VERSION 5.7 ;
  NOWIREEXTENSIONATPIN ON ;
  DIVIDERCHAR "/" ;
  BUSBITCHARS "[]" ;
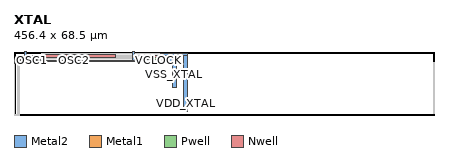
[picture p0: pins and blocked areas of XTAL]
MACRO XTAL
  CLASS BLOCK ;
  FOREIGN XTAL ;
  ORIGIN 0.000 0.000 ;
  SIZE 456.400 BY 68.500 ;
  PIN OSC2
    ANTENNAGATEAREA 2.352000 ;
    ANTENNADIFFAREA 48.399998 ;
    PORT
      LAYER Metal2 ;
        RECT 129.000 59.500 131.020 68.500 ;
        RECT 0.000 58.500 131.020 59.500 ;
        RECT 0.000 55.900 1.000 58.500 ;
    END
  END OSC2
  PIN VCLOCK
    ANTENNADIFFAREA 6.583500 ;
    PORT
      LAYER Metal1 ;
        RECT 143.910 63.165 144.140 64.020 ;
        RECT 145.510 63.165 145.740 64.020 ;
        RECT 147.110 63.165 147.340 64.020 ;
        RECT 143.910 62.935 147.340 63.165 ;
        RECT 147.110 62.665 147.340 62.935 ;
        RECT 148.725 62.665 148.955 64.020 ;
        RECT 150.325 62.665 150.555 64.020 ;
        RECT 151.925 62.665 152.155 64.020 ;
        RECT 147.110 62.600 152.155 62.665 ;
        RECT 147.110 62.250 167.075 62.600 ;
        RECT 147.110 62.160 152.155 62.250 ;
        RECT 147.110 61.960 147.340 62.160 ;
        RECT 143.910 61.730 147.340 61.960 ;
        RECT 143.910 61.160 144.140 61.730 ;
        RECT 145.510 61.160 145.740 61.730 ;
        RECT 147.110 61.160 147.340 61.730 ;
        RECT 148.725 61.160 148.955 62.160 ;
        RECT 150.325 61.160 150.555 62.160 ;
        RECT 151.925 61.160 152.155 62.160 ;
    END
  END VCLOCK
  PIN VSS_XTAL
    ANTENNADIFFAREA 40.156399 ;
    PORT
      LAYER Pwell ;
        RECT 137.295 60.200 156.115 62.400 ;
      LAYER Metal2 ;
        RECT 3.400 60.000 28.880 61.000 ;
        RECT 161.475 58.340 176.815 60.930 ;
        RECT 171.775 30.200 176.815 58.340 ;
    END
  END VSS_XTAL
  PIN VDD_XTAL
    ANTENNADIFFAREA 78.429695 ;
    PORT
      LAYER Nwell ;
        RECT 29.880 63.000 110.740 65.470 ;
        RECT 137.295 62.400 156.115 64.980 ;
      LAYER Metal2 ;
        RECT 158.655 64.250 189.075 66.835 ;
        RECT 184.075 4.045 189.075 64.250 ;
    END
  END VDD_XTAL
  PIN OSC1
    ANTENNAGATEAREA 30.799999 ;
    PORT
      LAYER Metal2 ;
        RECT 11.510 64.150 13.380 68.500 ;
        RECT 5.230 62.250 25.880 64.150 ;
    END
  END OSC1
  OBS
      LAYER Metal1 ;
        RECT 30.300 64.250 160.625 66.835 ;
        RECT 30.300 64.220 110.320 64.250 ;
        RECT 0.000 0.750 1.000 59.500 ;
        RECT 3.400 1.100 4.600 61.000 ;
        RECT 5.230 56.405 5.730 64.150 ;
        RECT 25.380 62.250 29.380 64.150 ;
        RECT 28.290 61.360 29.380 62.250 ;
        RECT 30.300 62.535 137.295 63.800 ;
        RECT 138.100 62.865 138.440 64.250 ;
        RECT 139.910 63.480 140.140 64.250 ;
        RECT 140.710 63.165 140.940 64.020 ;
        RECT 141.510 63.395 141.740 64.250 ;
        RECT 142.310 63.165 142.540 64.020 ;
        RECT 143.110 63.400 143.340 64.250 ;
        RECT 144.710 63.400 144.940 64.250 ;
        RECT 146.310 63.395 146.540 64.250 ;
        RECT 140.710 62.935 143.310 63.165 ;
        RECT 140.220 62.535 142.850 62.705 ;
        RECT 30.300 62.285 142.850 62.535 ;
        RECT 30.300 62.090 137.295 62.285 ;
        RECT 140.220 62.200 142.850 62.285 ;
        RECT 143.080 62.550 143.310 62.935 ;
        RECT 147.910 62.895 148.140 64.250 ;
        RECT 149.525 62.895 149.755 64.250 ;
        RECT 151.125 62.895 151.355 64.250 ;
        RECT 152.725 62.895 152.955 64.250 ;
        RECT 154.940 62.865 155.280 64.250 ;
        RECT 143.080 62.260 146.880 62.550 ;
        RECT 30.100 61.710 137.295 62.090 ;
        RECT 30.100 61.000 60.340 61.290 ;
        RECT 27.880 60.930 60.340 61.000 ;
        RECT 138.100 60.930 138.440 62.010 ;
        RECT 143.080 61.960 143.310 62.260 ;
        RECT 140.710 61.730 143.310 61.960 ;
        RECT 139.910 60.930 140.140 61.330 ;
        RECT 140.710 61.160 140.940 61.730 ;
        RECT 141.510 60.930 141.740 61.340 ;
        RECT 142.310 61.160 142.540 61.730 ;
        RECT 143.110 60.930 143.340 61.340 ;
        RECT 144.710 60.930 144.940 61.340 ;
        RECT 146.310 60.930 146.540 61.340 ;
        RECT 147.910 60.930 148.140 61.320 ;
        RECT 149.525 60.930 149.755 61.320 ;
        RECT 151.125 60.930 151.355 61.320 ;
        RECT 152.725 60.930 152.955 61.320 ;
        RECT 154.940 60.930 155.280 62.010 ;
        RECT 27.880 58.340 163.475 60.930 ;
        RECT 5.380 52.595 5.730 55.345 ;
        RECT 456.050 54.495 456.400 57.245 ;
        RECT 5.380 48.795 5.730 51.545 ;
        RECT 456.050 50.695 456.400 53.445 ;
        RECT 5.380 44.995 5.730 47.745 ;
        RECT 456.050 46.895 456.400 49.645 ;
        RECT 5.380 41.195 5.730 43.945 ;
        RECT 456.050 43.095 456.400 45.845 ;
        RECT 5.380 37.395 5.730 40.145 ;
        RECT 456.050 39.295 456.400 42.045 ;
        RECT 5.380 33.595 5.730 36.345 ;
        RECT 456.050 35.495 456.400 38.245 ;
        RECT 5.380 29.795 5.730 32.545 ;
        RECT 456.050 31.695 456.400 34.445 ;
        RECT 5.380 25.995 5.730 28.745 ;
        RECT 456.050 27.895 456.400 30.645 ;
        RECT 5.380 22.195 5.730 24.945 ;
        RECT 456.050 24.095 456.400 26.845 ;
        RECT 5.380 18.395 5.730 21.145 ;
        RECT 456.050 20.295 456.400 23.045 ;
        RECT 5.380 14.595 5.730 17.345 ;
        RECT 456.050 16.495 456.400 19.245 ;
        RECT 5.380 10.795 5.730 13.545 ;
        RECT 456.050 12.695 456.400 15.445 ;
        RECT 5.380 6.995 5.730 9.745 ;
        RECT 456.050 8.895 456.400 11.645 ;
        RECT 5.380 3.195 5.730 5.945 ;
        RECT 456.050 5.095 456.400 7.845 ;
        RECT 5.300 0.750 5.730 2.200 ;
        RECT 456.050 1.295 456.400 4.045 ;
        RECT 0.000 0.000 5.730 0.750 ;
      LAYER Via1 ;
        RECT 158.930 66.370 159.190 66.630 ;
        RECT 159.475 66.370 159.735 66.630 ;
        RECT 160.035 66.370 160.295 66.630 ;
        RECT 158.935 65.720 159.195 65.980 ;
        RECT 159.475 65.720 159.735 65.980 ;
        RECT 160.035 65.720 160.295 65.980 ;
        RECT 158.935 65.120 159.195 65.380 ;
        RECT 159.475 65.120 159.735 65.380 ;
        RECT 160.035 65.120 160.295 65.380 ;
        RECT 158.935 64.520 159.195 64.780 ;
        RECT 159.475 64.520 159.735 64.780 ;
        RECT 160.035 64.520 160.295 64.780 ;
        RECT 5.350 63.690 5.610 63.950 ;
        RECT 5.350 63.070 5.610 63.330 ;
        RECT 5.350 62.450 5.610 62.710 ;
        RECT 3.600 60.540 3.860 60.800 ;
        RECT 4.140 60.200 4.400 60.460 ;
        RECT 0.100 59.040 0.360 59.300 ;
        RECT 0.640 59.040 0.900 59.300 ;
        RECT 0.100 58.440 0.360 58.700 ;
        RECT 0.640 58.440 0.900 58.700 ;
        RECT 0.100 57.840 0.360 58.100 ;
        RECT 0.640 57.840 0.900 58.100 ;
        RECT 0.100 57.240 0.360 57.500 ;
        RECT 0.640 57.240 0.900 57.500 ;
        RECT 0.100 56.640 0.360 56.900 ;
        RECT 0.640 56.640 0.900 56.900 ;
        RECT 0.100 56.040 0.360 56.300 ;
        RECT 0.640 56.040 0.900 56.300 ;
        RECT 25.500 63.680 25.760 63.940 ;
        RECT 25.500 63.060 25.760 63.320 ;
        RECT 25.500 62.450 25.760 62.710 ;
        RECT 129.260 63.220 129.520 63.480 ;
        RECT 129.860 63.220 130.120 63.480 ;
        RECT 130.460 63.220 130.720 63.480 ;
        RECT 129.260 62.560 129.520 62.820 ;
        RECT 129.860 62.560 130.120 62.820 ;
        RECT 130.460 62.560 130.720 62.820 ;
        RECT 129.260 61.920 129.520 62.180 ;
        RECT 129.860 61.920 130.120 62.180 ;
        RECT 130.460 61.920 130.720 62.180 ;
        RECT 28.020 60.600 28.280 60.860 ;
        RECT 161.775 60.370 162.035 60.630 ;
        RECT 162.315 60.370 162.575 60.630 ;
        RECT 162.875 60.370 163.135 60.630 ;
        RECT 28.520 60.100 28.780 60.360 ;
        RECT 161.775 59.770 162.035 60.030 ;
        RECT 162.315 59.770 162.575 60.030 ;
        RECT 162.875 59.770 163.135 60.030 ;
        RECT 161.775 59.170 162.035 59.430 ;
        RECT 162.315 59.170 162.575 59.430 ;
        RECT 162.875 59.170 163.135 59.430 ;
        RECT 161.775 58.620 162.035 58.880 ;
        RECT 162.315 58.620 162.575 58.880 ;
        RECT 162.875 58.620 163.135 58.880 ;
  END
END XTAL
END LIBRARY

